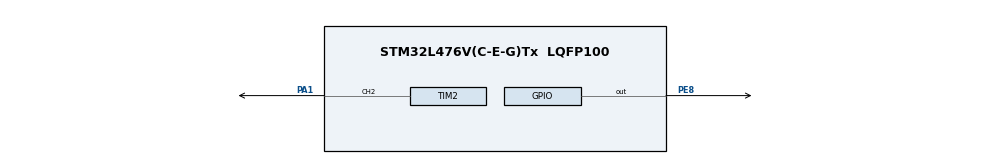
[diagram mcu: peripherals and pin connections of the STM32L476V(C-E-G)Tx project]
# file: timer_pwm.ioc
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Mcu.Family=STM32L4
Mcu.Name=STM32L476V(C-E-G)Tx
Mcu.Package=LQFP100
NVIC.PriorityGroup=NVIC_PRIORITYGROUP_4
NVIC.TIM2_IRQn=true\:0\:0\:false\:false\:true\:true\:true
PA1.Signal=S_TIM2_CH2
PE8.Signal=GPIO_Output
ProjectManager.HeapSize=0x200
ProjectManager.StackSize=0x400
ProjectManager.TargetToolchain=EWARM V8
RCC.ADCFreq_Value=192000000
RCC.AHBFreq_Value=48000000
RCC.APB1Freq_Value=48000000
RCC.APB1TimFreq_Value=48000000
RCC.APB2Freq_Value=48000000
RCC.APB2TimFreq_Value=48000000
RCC.CortexFreq_Value=48000000
RCC.HCLKFreq_Value=48000000
RCC.HSE_VALUE=8000000
RCC.HSI_VALUE=16000000
RCC.LSE_VALUE=32768
RCC.MSIClockRange=RCC_MSIRANGE_11
RCC.MSI_VALUE=48000000
RCC.SYSCLKFreq_VALUE=48000000
RCC.USBFreq_Value=192000000
RCC.VCOOutputFreq_Value=384000000
SH.S_TIM2_CH2.0=TIM2_CH2,PWM Generation2 CH2
TIM2.Channel-PWM\ Generation2\ CH2=TIM_CHANNEL_2
board=custom

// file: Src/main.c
/* USER CODE BEGIN Header */
/**
  ******************************************************************************
  * @file           : main.c
  * @brief          : Main program body
  ******************************************************************************
  * @attention
  *
  * <h2><center>&copy; Copyright (c) 2019 STMicroelectronics.
  * All rights reserved.</center></h2>
  *
  * This software component is licensed by ST under BSD 3-Clause license,
  * the "License"; You may not use this file except in compliance with the
  * License. You may obtain a copy of the License at:
  *                        opensource.org/licenses/BSD-3-Clause
  *
  ******************************************************************************
  */
/* USER CODE END Header */

#include "main.h"

TIM_HandleTypeDef htim2;

/* USER CODE BEGIN PV */
int pwm = 0;
/* USER CODE END PV */

void SystemClock_Config(void);
static void MX_GPIO_Init(void);
static void MX_TIM2_Init(void);

int main(void)
{

  /* MCU Configuration--------------------------------------------------------*/

  /* Reset of all peripherals, Initializes the Flash interface and the Systick. */
  HAL_Init();

  /* Configure the system clock */
  SystemClock_Config();

  /* Initialize all configured peripherals */
  MX_GPIO_Init();
  MX_TIM2_Init();
  __HAL_TIM_ENABLE_IT(&htim2, TIM_IT_CC2);
  /* USER CODE BEGIN 2 */
  HAL_TIM_PWM_Start(&htim2, TIM_CHANNEL_2);
  /* USER CODE END 2 */

  /* Infinite loop */
  /* USER CODE BEGIN WHILE */
  while (1)
  {
//    printf("Running in while(1)\n");
//    for (pwm=0; pwm<=200; pwm++)  //darkest to brightest: 0-100% duty cycle
//    {
//      __HAL_TIM_SetCompare(&htim2, TIM_CHANNEL_2, pwm);
//      HAL_Delay(10);
//    }
//
//    HAL_Delay(400);
//
//    for (pwm=200; pwm>=0 ;pwm--)  //brightest to darkest: 100-0% duty cycle
//    {
//      __HAL_TIM_SetCompare(&htim2, TIM_CHANNEL_2, pwm);
//      HAL_Delay(10);
//    }
//
//    HAL_Delay(400);
    /* USER CODE END WHILE */

  }
}

void SystemClock_Config(void)
{
  RCC_ClkInitTypeDef RCC_ClkInitStruct = {0};
  RCC_OscInitTypeDef RCC_OscInitStruct = {0};

  /* MSI is enabled after System reset, activate PLL with MSI as source */
  RCC_OscInitStruct.OscillatorType = RCC_OSCILLATORTYPE_MSI;
  RCC_OscInitStruct.MSIState = RCC_MSI_ON;
  RCC_OscInitStruct.MSIClockRange = RCC_MSIRANGE_6;
  RCC_OscInitStruct.MSICalibrationValue = RCC_MSICALIBRATION_DEFAULT;
  RCC_OscInitStruct.PLL.PLLState = RCC_PLL_ON;
  RCC_OscInitStruct.PLL.PLLSource = RCC_PLLSOURCE_MSI;
  RCC_OscInitStruct.PLL.PLLM = 1;
  RCC_OscInitStruct.PLL.PLLN = 40;
  RCC_OscInitStruct.PLL.PLLR = 2;
  RCC_OscInitStruct.PLL.PLLP = 7;
  RCC_OscInitStruct.PLL.PLLQ = 4;
  if(HAL_RCC_OscConfig(&RCC_OscInitStruct) != HAL_OK)
  {
    /* Initialization Error */
    while(1);
  }

  /* Select PLL as system clock source and configure the HCLK, PCLK1 and PCLK2
     clocks dividers */
  RCC_ClkInitStruct.ClockType = (RCC_CLOCKTYPE_SYSCLK | RCC_CLOCKTYPE_HCLK | RCC_CLOCKTYPE_PCLK1 | RCC_CLOCKTYPE_PCLK2);
  RCC_ClkInitStruct.SYSCLKSource = RCC_SYSCLKSOURCE_PLLCLK;
  RCC_ClkInitStruct.AHBCLKDivider = RCC_SYSCLK_DIV1;
  RCC_ClkInitStruct.APB1CLKDivider = RCC_HCLK_DIV1;
  RCC_ClkInitStruct.APB2CLKDivider = RCC_HCLK_DIV1;
  if(HAL_RCC_ClockConfig(&RCC_ClkInitStruct, FLASH_LATENCY_4) != HAL_OK)
  {
    /* Initialization Error */
    while(1);
  }
}

static void MX_TIM2_Init(void)
{

  TIM_MasterConfigTypeDef sMasterConfig = {0};
  TIM_OC_InitTypeDef sConfigOC = {0};

  htim2.Instance = TIM2;
  htim2.Init.Prescaler = 2;
  htim2.Init.CounterMode = TIM_COUNTERMODE_UP;
  htim2.Init.Period = 100;
  htim2.Init.ClockDivision = TIM_CLOCKDIVISION_DIV1;
  htim2.Init.AutoReloadPreload = TIM_AUTORELOAD_PRELOAD_DISABLE;
  if (HAL_TIM_PWM_Init(&htim2) != HAL_OK)
  {
    Error_Handler();
  }
  sMasterConfig.MasterOutputTrigger = TIM_TRGO_RESET;
  sMasterConfig.MasterSlaveMode = TIM_MASTERSLAVEMODE_DISABLE;
  if (HAL_TIMEx_MasterConfigSynchronization(&htim2, &sMasterConfig) != HAL_OK)
  {
    Error_Handler();
  }
  sConfigOC.OCMode = TIM_OCMODE_PWM1;
  sConfigOC.Pulse = 200;
  sConfigOC.OCPolarity = TIM_OCPOLARITY_HIGH;
  sConfigOC.OCFastMode = TIM_OCFAST_DISABLE;
  if (HAL_TIM_PWM_ConfigChannel(&htim2, &sConfigOC, TIM_CHANNEL_2) != HAL_OK)
  {
    Error_Handler();
  }
  HAL_TIM_MspPostInit(&htim2);

}

static void MX_GPIO_Init(void)
{
  GPIO_InitTypeDef GPIO_InitStruct = {0};

  /* GPIO Ports Clock Enable */
  __HAL_RCC_GPIOA_CLK_ENABLE();
  __HAL_RCC_GPIOE_CLK_ENABLE();

  /*Configure GPIO pin Output Level */
  HAL_GPIO_WritePin(GPIOE, GPIO_PIN_8, GPIO_PIN_RESET);

  /*Configure GPIO pin : PE8 */
  GPIO_InitStruct.Pin = GPIO_PIN_8;
  GPIO_InitStruct.Mode = GPIO_MODE_OUTPUT_PP;
  GPIO_InitStruct.Pull = GPIO_NOPULL;
  GPIO_InitStruct.Speed = GPIO_SPEED_FREQ_LOW;
  HAL_GPIO_Init(GPIOE, &GPIO_InitStruct);

}

void Error_Handler(void)
{
  /* USER CODE BEGIN Error_Handler_Debug */
  /* User can add his own implementation to report the HAL error return state */
  printf("Error_Handler\n");
  /* USER CODE END Error_Handler_Debug */
}

/************************ (C) COPYRIGHT STMicroelectronics *****END OF FILE****/
